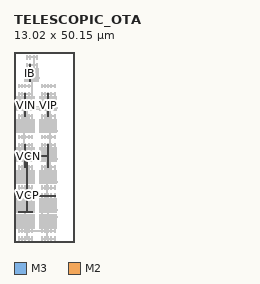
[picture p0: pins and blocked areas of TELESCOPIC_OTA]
MACRO TELESCOPIC_OTA
  ORIGIN 0 0 ;
  FOREIGN TELESCOPIC_OTA 0 0 ;
  SIZE 13.02 BY 50.15 ;
  PIN IB
    DIRECTION INOUT ;
    USE SIGNAL ;
    PORT 
      LAYER M3 ;
        RECT 4.16 42.26 4.44 46.78 ;
    END
  END IB
  PIN VCN
    DIRECTION INOUT ;
    USE SIGNAL ;
    PORT 
      LAYER M3 ;
        RECT 2.87 19.58 3.15 25.78 ;
      LAYER M3 ;
        RECT 8.89 19.58 9.17 25.78 ;
      LAYER M3 ;
        RECT 2.87 22.495 3.15 22.865 ;
      LAYER M2 ;
        RECT 3.01 22.54 9.03 22.82 ;
      LAYER M3 ;
        RECT 8.89 22.495 9.17 22.865 ;
    END
  END VCN
  PIN VOUT
    DIRECTION INOUT ;
    USE SIGNAL ;
    PORT 
      LAYER M2 ;
        RECT 1.12 7.84 4.9 8.12 ;
      LAYER M3 ;
        RECT 3.3 15.38 3.58 21.58 ;
      LAYER M2 ;
        RECT 3.28 7.84 3.6 8.12 ;
      LAYER M3 ;
        RECT 3.3 7.98 3.58 15.54 ;
    END
  END VOUT
  PIN VIP
    DIRECTION INOUT ;
    USE SIGNAL ;
    PORT 
      LAYER M3 ;
        RECT 8.89 33.02 9.17 39.22 ;
    END
  END VIP
  PIN VIN
    DIRECTION INOUT ;
    USE SIGNAL ;
    PORT 
      LAYER M3 ;
        RECT 2.87 33.02 3.15 39.22 ;
    END
  END VIN
  PIN VCP
    DIRECTION INOUT ;
    USE SIGNAL ;
    PORT 
      LAYER M2 ;
        RECT 1.12 12.04 4.9 12.32 ;
      LAYER M2 ;
        RECT 7.14 12.04 10.92 12.32 ;
      LAYER M2 ;
        RECT 4.73 12.04 7.31 12.32 ;
    END
  END VCP
  OBS 
  LAYER M3 ;
        RECT 3.3 29.24 3.58 35.44 ;
  LAYER M3 ;
        RECT 8.46 29.24 8.74 35.44 ;
  LAYER M2 ;
        RECT 4.13 42.7 5.33 42.98 ;
  LAYER M3 ;
        RECT 3.3 35.095 3.58 35.465 ;
  LAYER M4 ;
        RECT 3.44 34.88 8.6 35.68 ;
  LAYER M3 ;
        RECT 8.46 35.095 8.74 35.465 ;
  LAYER M4 ;
        RECT 4.565 34.88 4.895 35.68 ;
  LAYER M3 ;
        RECT 4.59 35.28 4.87 42.84 ;
  LAYER M2 ;
        RECT 4.57 42.7 4.89 42.98 ;
  LAYER M3 ;
        RECT 3.3 35.095 3.58 35.465 ;
  LAYER M4 ;
        RECT 3.275 34.88 3.605 35.68 ;
  LAYER M3 ;
        RECT 8.46 35.095 8.74 35.465 ;
  LAYER M4 ;
        RECT 8.435 34.88 8.765 35.68 ;
  LAYER M3 ;
        RECT 3.3 35.095 3.58 35.465 ;
  LAYER M4 ;
        RECT 3.275 34.88 3.605 35.68 ;
  LAYER M3 ;
        RECT 8.46 35.095 8.74 35.465 ;
  LAYER M4 ;
        RECT 8.435 34.88 8.765 35.68 ;
  LAYER M2 ;
        RECT 4.57 42.7 4.89 42.98 ;
  LAYER M3 ;
        RECT 4.59 42.68 4.87 43 ;
  LAYER M3 ;
        RECT 3.3 35.095 3.58 35.465 ;
  LAYER M4 ;
        RECT 3.275 34.88 3.605 35.68 ;
  LAYER M3 ;
        RECT 4.59 35.095 4.87 35.465 ;
  LAYER M4 ;
        RECT 4.565 34.88 4.895 35.68 ;
  LAYER M3 ;
        RECT 8.46 35.095 8.74 35.465 ;
  LAYER M4 ;
        RECT 8.435 34.88 8.765 35.68 ;
  LAYER M2 ;
        RECT 4.57 42.7 4.89 42.98 ;
  LAYER M3 ;
        RECT 4.59 42.68 4.87 43 ;
  LAYER M3 ;
        RECT 3.3 35.095 3.58 35.465 ;
  LAYER M4 ;
        RECT 3.275 34.88 3.605 35.68 ;
  LAYER M3 ;
        RECT 4.59 35.095 4.87 35.465 ;
  LAYER M4 ;
        RECT 4.565 34.88 4.895 35.68 ;
  LAYER M3 ;
        RECT 8.46 35.095 8.74 35.465 ;
  LAYER M4 ;
        RECT 8.435 34.88 8.765 35.68 ;
  LAYER M2 ;
        RECT 7.14 7 10.92 7.28 ;
  LAYER M2 ;
        RECT 6.71 8.26 11.35 8.54 ;
  LAYER M2 ;
        RECT 8.87 7 9.19 7.28 ;
  LAYER M3 ;
        RECT 8.89 7.14 9.17 8.4 ;
  LAYER M2 ;
        RECT 8.87 8.26 9.19 8.54 ;
  LAYER M2 ;
        RECT 8.87 7 9.19 7.28 ;
  LAYER M3 ;
        RECT 8.89 6.98 9.17 7.3 ;
  LAYER M2 ;
        RECT 8.87 8.26 9.19 8.54 ;
  LAYER M3 ;
        RECT 8.89 8.24 9.17 8.56 ;
  LAYER M2 ;
        RECT 8.87 7 9.19 7.28 ;
  LAYER M3 ;
        RECT 8.89 6.98 9.17 7.3 ;
  LAYER M2 ;
        RECT 8.87 8.26 9.19 8.54 ;
  LAYER M3 ;
        RECT 8.89 8.24 9.17 8.56 ;
  LAYER M2 ;
        RECT 1.12 2.8 4.9 3.08 ;
  LAYER M2 ;
        RECT 7.14 2.8 10.92 3.08 ;
  LAYER M2 ;
        RECT 7.14 7.84 10.92 8.12 ;
  LAYER M3 ;
        RECT 8.46 15.38 8.74 21.58 ;
  LAYER M2 ;
        RECT 4.73 2.8 7.31 3.08 ;
  LAYER M2 ;
        RECT 7.15 2.8 7.47 3.08 ;
  LAYER M3 ;
        RECT 7.17 2.94 7.45 7.98 ;
  LAYER M2 ;
        RECT 7.15 7.84 7.47 8.12 ;
  LAYER M2 ;
        RECT 8.44 7.84 8.76 8.12 ;
  LAYER M3 ;
        RECT 8.46 7.98 8.74 15.54 ;
  LAYER M2 ;
        RECT 7.15 2.8 7.47 3.08 ;
  LAYER M3 ;
        RECT 7.17 2.78 7.45 3.1 ;
  LAYER M2 ;
        RECT 7.15 7.84 7.47 8.12 ;
  LAYER M3 ;
        RECT 7.17 7.82 7.45 8.14 ;
  LAYER M2 ;
        RECT 7.15 2.8 7.47 3.08 ;
  LAYER M3 ;
        RECT 7.17 2.78 7.45 3.1 ;
  LAYER M2 ;
        RECT 7.15 7.84 7.47 8.12 ;
  LAYER M3 ;
        RECT 7.17 7.82 7.45 8.14 ;
  LAYER M2 ;
        RECT 7.15 2.8 7.47 3.08 ;
  LAYER M3 ;
        RECT 7.17 2.78 7.45 3.1 ;
  LAYER M2 ;
        RECT 7.15 7.84 7.47 8.12 ;
  LAYER M3 ;
        RECT 7.17 7.82 7.45 8.14 ;
  LAYER M2 ;
        RECT 8.44 7.84 8.76 8.12 ;
  LAYER M3 ;
        RECT 8.46 7.82 8.74 8.14 ;
  LAYER M2 ;
        RECT 7.15 2.8 7.47 3.08 ;
  LAYER M3 ;
        RECT 7.17 2.78 7.45 3.1 ;
  LAYER M2 ;
        RECT 7.15 7.84 7.47 8.12 ;
  LAYER M3 ;
        RECT 7.17 7.82 7.45 8.14 ;
  LAYER M2 ;
        RECT 8.44 7.84 8.76 8.12 ;
  LAYER M3 ;
        RECT 8.46 7.82 8.74 8.14 ;
  LAYER M2 ;
        RECT 1.12 7 4.9 7.28 ;
  LAYER M2 ;
        RECT 0.69 8.26 5.33 8.54 ;
  LAYER M2 ;
        RECT 2.85 7 3.17 7.28 ;
  LAYER M3 ;
        RECT 2.87 7.14 3.15 8.4 ;
  LAYER M2 ;
        RECT 2.85 8.26 3.17 8.54 ;
  LAYER M2 ;
        RECT 2.85 7 3.17 7.28 ;
  LAYER M3 ;
        RECT 2.87 6.98 3.15 7.3 ;
  LAYER M2 ;
        RECT 2.85 8.26 3.17 8.54 ;
  LAYER M3 ;
        RECT 2.87 8.24 3.15 8.56 ;
  LAYER M2 ;
        RECT 2.85 7 3.17 7.28 ;
  LAYER M3 ;
        RECT 2.87 6.98 3.15 7.3 ;
  LAYER M2 ;
        RECT 2.85 8.26 3.17 8.54 ;
  LAYER M3 ;
        RECT 2.87 8.24 3.15 8.56 ;
  LAYER M3 ;
        RECT 9.32 15.8 9.6 22 ;
  LAYER M3 ;
        RECT 9.32 28.82 9.6 35.02 ;
  LAYER M3 ;
        RECT 9.32 21.84 9.6 28.98 ;
  LAYER M3 ;
        RECT 2.44 15.8 2.72 22 ;
  LAYER M3 ;
        RECT 2.44 28.82 2.72 35.02 ;
  LAYER M3 ;
        RECT 2.44 21.84 2.72 28.98 ;
  LAYER M1 ;
        RECT 3.315 42.335 3.565 45.865 ;
  LAYER M1 ;
        RECT 3.315 46.115 3.565 47.125 ;
  LAYER M1 ;
        RECT 3.315 48.215 3.565 49.225 ;
  LAYER M1 ;
        RECT 2.885 42.335 3.135 45.865 ;
  LAYER M1 ;
        RECT 3.745 42.335 3.995 45.865 ;
  LAYER M1 ;
        RECT 4.175 42.335 4.425 45.865 ;
  LAYER M1 ;
        RECT 4.175 46.115 4.425 47.125 ;
  LAYER M1 ;
        RECT 4.175 48.215 4.425 49.225 ;
  LAYER M1 ;
        RECT 4.605 42.335 4.855 45.865 ;
  LAYER M1 ;
        RECT 5.035 42.335 5.285 45.865 ;
  LAYER M1 ;
        RECT 5.035 46.115 5.285 47.125 ;
  LAYER M1 ;
        RECT 5.035 48.215 5.285 49.225 ;
  LAYER M1 ;
        RECT 5.465 42.335 5.715 45.865 ;
  LAYER M1 ;
        RECT 5.895 42.335 6.145 45.865 ;
  LAYER M1 ;
        RECT 5.895 46.115 6.145 47.125 ;
  LAYER M1 ;
        RECT 5.895 48.215 6.145 49.225 ;
  LAYER M1 ;
        RECT 6.325 42.335 6.575 45.865 ;
  LAYER M2 ;
        RECT 3.27 42.28 6.19 42.56 ;
  LAYER M2 ;
        RECT 3.27 46.48 6.19 46.76 ;
  LAYER M2 ;
        RECT 2.84 43.12 6.62 43.4 ;
  LAYER M2 ;
        RECT 3.27 48.58 6.19 48.86 ;
  LAYER M3 ;
        RECT 4.16 42.26 4.44 46.78 ;
  LAYER M2 ;
        RECT 4.13 42.7 5.33 42.98 ;
  LAYER M3 ;
        RECT 5.02 43.1 5.3 48.88 ;
  LAYER M1 ;
        RECT 10.625 3.695 10.875 7.225 ;
  LAYER M1 ;
        RECT 10.625 2.435 10.875 3.445 ;
  LAYER M1 ;
        RECT 10.625 0.335 10.875 1.345 ;
  LAYER M1 ;
        RECT 11.055 3.695 11.305 7.225 ;
  LAYER M1 ;
        RECT 10.195 3.695 10.445 7.225 ;
  LAYER M1 ;
        RECT 9.765 3.695 10.015 7.225 ;
  LAYER M1 ;
        RECT 9.765 2.435 10.015 3.445 ;
  LAYER M1 ;
        RECT 9.765 0.335 10.015 1.345 ;
  LAYER M1 ;
        RECT 9.335 3.695 9.585 7.225 ;
  LAYER M1 ;
        RECT 8.905 3.695 9.155 7.225 ;
  LAYER M1 ;
        RECT 8.905 2.435 9.155 3.445 ;
  LAYER M1 ;
        RECT 8.905 0.335 9.155 1.345 ;
  LAYER M1 ;
        RECT 8.475 3.695 8.725 7.225 ;
  LAYER M1 ;
        RECT 8.045 3.695 8.295 7.225 ;
  LAYER M1 ;
        RECT 8.045 2.435 8.295 3.445 ;
  LAYER M1 ;
        RECT 8.045 0.335 8.295 1.345 ;
  LAYER M1 ;
        RECT 7.615 3.695 7.865 7.225 ;
  LAYER M1 ;
        RECT 7.185 3.695 7.435 7.225 ;
  LAYER M1 ;
        RECT 7.185 2.435 7.435 3.445 ;
  LAYER M1 ;
        RECT 7.185 0.335 7.435 1.345 ;
  LAYER M1 ;
        RECT 6.755 3.695 7.005 7.225 ;
  LAYER M2 ;
        RECT 6.71 6.58 11.35 6.86 ;
  LAYER M2 ;
        RECT 7.14 0.7 10.92 0.98 ;
  LAYER M2 ;
        RECT 7.14 7 10.92 7.28 ;
  LAYER M2 ;
        RECT 7.14 2.8 10.92 3.08 ;
  LAYER M3 ;
        RECT 8.46 0.68 8.74 6.88 ;
  LAYER M1 ;
        RECT 1.165 3.695 1.415 7.225 ;
  LAYER M1 ;
        RECT 1.165 2.435 1.415 3.445 ;
  LAYER M1 ;
        RECT 1.165 0.335 1.415 1.345 ;
  LAYER M1 ;
        RECT 0.735 3.695 0.985 7.225 ;
  LAYER M1 ;
        RECT 1.595 3.695 1.845 7.225 ;
  LAYER M1 ;
        RECT 2.025 3.695 2.275 7.225 ;
  LAYER M1 ;
        RECT 2.025 2.435 2.275 3.445 ;
  LAYER M1 ;
        RECT 2.025 0.335 2.275 1.345 ;
  LAYER M1 ;
        RECT 2.455 3.695 2.705 7.225 ;
  LAYER M1 ;
        RECT 2.885 3.695 3.135 7.225 ;
  LAYER M1 ;
        RECT 2.885 2.435 3.135 3.445 ;
  LAYER M1 ;
        RECT 2.885 0.335 3.135 1.345 ;
  LAYER M1 ;
        RECT 3.315 3.695 3.565 7.225 ;
  LAYER M1 ;
        RECT 3.745 3.695 3.995 7.225 ;
  LAYER M1 ;
        RECT 3.745 2.435 3.995 3.445 ;
  LAYER M1 ;
        RECT 3.745 0.335 3.995 1.345 ;
  LAYER M1 ;
        RECT 4.175 3.695 4.425 7.225 ;
  LAYER M1 ;
        RECT 4.605 3.695 4.855 7.225 ;
  LAYER M1 ;
        RECT 4.605 2.435 4.855 3.445 ;
  LAYER M1 ;
        RECT 4.605 0.335 4.855 1.345 ;
  LAYER M1 ;
        RECT 5.035 3.695 5.285 7.225 ;
  LAYER M2 ;
        RECT 0.69 6.58 5.33 6.86 ;
  LAYER M2 ;
        RECT 1.12 0.7 4.9 0.98 ;
  LAYER M2 ;
        RECT 1.12 7 4.9 7.28 ;
  LAYER M2 ;
        RECT 1.12 2.8 4.9 3.08 ;
  LAYER M3 ;
        RECT 3.3 0.68 3.58 6.88 ;
  LAYER M1 ;
        RECT 7.185 15.455 7.435 18.985 ;
  LAYER M1 ;
        RECT 7.185 19.235 7.435 20.245 ;
  LAYER M1 ;
        RECT 7.185 21.335 7.435 24.865 ;
  LAYER M1 ;
        RECT 7.185 25.115 7.435 26.125 ;
  LAYER M1 ;
        RECT 7.185 27.215 7.435 28.225 ;
  LAYER M1 ;
        RECT 6.755 15.455 7.005 18.985 ;
  LAYER M1 ;
        RECT 6.755 21.335 7.005 24.865 ;
  LAYER M1 ;
        RECT 7.615 15.455 7.865 18.985 ;
  LAYER M1 ;
        RECT 7.615 21.335 7.865 24.865 ;
  LAYER M1 ;
        RECT 8.045 15.455 8.295 18.985 ;
  LAYER M1 ;
        RECT 8.045 19.235 8.295 20.245 ;
  LAYER M1 ;
        RECT 8.045 21.335 8.295 24.865 ;
  LAYER M1 ;
        RECT 8.045 25.115 8.295 26.125 ;
  LAYER M1 ;
        RECT 8.045 27.215 8.295 28.225 ;
  LAYER M1 ;
        RECT 8.475 15.455 8.725 18.985 ;
  LAYER M1 ;
        RECT 8.475 21.335 8.725 24.865 ;
  LAYER M1 ;
        RECT 8.905 15.455 9.155 18.985 ;
  LAYER M1 ;
        RECT 8.905 19.235 9.155 20.245 ;
  LAYER M1 ;
        RECT 8.905 21.335 9.155 24.865 ;
  LAYER M1 ;
        RECT 8.905 25.115 9.155 26.125 ;
  LAYER M1 ;
        RECT 8.905 27.215 9.155 28.225 ;
  LAYER M1 ;
        RECT 9.335 15.455 9.585 18.985 ;
  LAYER M1 ;
        RECT 9.335 21.335 9.585 24.865 ;
  LAYER M1 ;
        RECT 9.765 15.455 10.015 18.985 ;
  LAYER M1 ;
        RECT 9.765 19.235 10.015 20.245 ;
  LAYER M1 ;
        RECT 9.765 21.335 10.015 24.865 ;
  LAYER M1 ;
        RECT 9.765 25.115 10.015 26.125 ;
  LAYER M1 ;
        RECT 9.765 27.215 10.015 28.225 ;
  LAYER M1 ;
        RECT 10.195 15.455 10.445 18.985 ;
  LAYER M1 ;
        RECT 10.195 21.335 10.445 24.865 ;
  LAYER M1 ;
        RECT 10.625 15.455 10.875 18.985 ;
  LAYER M1 ;
        RECT 10.625 19.235 10.875 20.245 ;
  LAYER M1 ;
        RECT 10.625 21.335 10.875 24.865 ;
  LAYER M1 ;
        RECT 10.625 25.115 10.875 26.125 ;
  LAYER M1 ;
        RECT 10.625 27.215 10.875 28.225 ;
  LAYER M1 ;
        RECT 11.055 15.455 11.305 18.985 ;
  LAYER M1 ;
        RECT 11.055 21.335 11.305 24.865 ;
  LAYER M2 ;
        RECT 7.14 15.4 10.92 15.68 ;
  LAYER M2 ;
        RECT 7.14 19.6 10.92 19.88 ;
  LAYER M2 ;
        RECT 6.71 15.82 11.35 16.1 ;
  LAYER M2 ;
        RECT 7.14 21.28 10.92 21.56 ;
  LAYER M2 ;
        RECT 7.14 25.48 10.92 25.76 ;
  LAYER M2 ;
        RECT 6.71 21.7 11.35 21.98 ;
  LAYER M2 ;
        RECT 7.14 27.58 10.92 27.86 ;
  LAYER M3 ;
        RECT 8.46 15.38 8.74 21.58 ;
  LAYER M3 ;
        RECT 8.89 19.58 9.17 25.78 ;
  LAYER M3 ;
        RECT 9.32 15.8 9.6 22 ;
  LAYER M1 ;
        RECT 4.605 15.455 4.855 18.985 ;
  LAYER M1 ;
        RECT 4.605 19.235 4.855 20.245 ;
  LAYER M1 ;
        RECT 4.605 21.335 4.855 24.865 ;
  LAYER M1 ;
        RECT 4.605 25.115 4.855 26.125 ;
  LAYER M1 ;
        RECT 4.605 27.215 4.855 28.225 ;
  LAYER M1 ;
        RECT 5.035 15.455 5.285 18.985 ;
  LAYER M1 ;
        RECT 5.035 21.335 5.285 24.865 ;
  LAYER M1 ;
        RECT 4.175 15.455 4.425 18.985 ;
  LAYER M1 ;
        RECT 4.175 21.335 4.425 24.865 ;
  LAYER M1 ;
        RECT 3.745 15.455 3.995 18.985 ;
  LAYER M1 ;
        RECT 3.745 19.235 3.995 20.245 ;
  LAYER M1 ;
        RECT 3.745 21.335 3.995 24.865 ;
  LAYER M1 ;
        RECT 3.745 25.115 3.995 26.125 ;
  LAYER M1 ;
        RECT 3.745 27.215 3.995 28.225 ;
  LAYER M1 ;
        RECT 3.315 15.455 3.565 18.985 ;
  LAYER M1 ;
        RECT 3.315 21.335 3.565 24.865 ;
  LAYER M1 ;
        RECT 2.885 15.455 3.135 18.985 ;
  LAYER M1 ;
        RECT 2.885 19.235 3.135 20.245 ;
  LAYER M1 ;
        RECT 2.885 21.335 3.135 24.865 ;
  LAYER M1 ;
        RECT 2.885 25.115 3.135 26.125 ;
  LAYER M1 ;
        RECT 2.885 27.215 3.135 28.225 ;
  LAYER M1 ;
        RECT 2.455 15.455 2.705 18.985 ;
  LAYER M1 ;
        RECT 2.455 21.335 2.705 24.865 ;
  LAYER M1 ;
        RECT 2.025 15.455 2.275 18.985 ;
  LAYER M1 ;
        RECT 2.025 19.235 2.275 20.245 ;
  LAYER M1 ;
        RECT 2.025 21.335 2.275 24.865 ;
  LAYER M1 ;
        RECT 2.025 25.115 2.275 26.125 ;
  LAYER M1 ;
        RECT 2.025 27.215 2.275 28.225 ;
  LAYER M1 ;
        RECT 1.595 15.455 1.845 18.985 ;
  LAYER M1 ;
        RECT 1.595 21.335 1.845 24.865 ;
  LAYER M1 ;
        RECT 1.165 15.455 1.415 18.985 ;
  LAYER M1 ;
        RECT 1.165 19.235 1.415 20.245 ;
  LAYER M1 ;
        RECT 1.165 21.335 1.415 24.865 ;
  LAYER M1 ;
        RECT 1.165 25.115 1.415 26.125 ;
  LAYER M1 ;
        RECT 1.165 27.215 1.415 28.225 ;
  LAYER M1 ;
        RECT 0.735 15.455 0.985 18.985 ;
  LAYER M1 ;
        RECT 0.735 21.335 0.985 24.865 ;
  LAYER M2 ;
        RECT 1.12 15.4 4.9 15.68 ;
  LAYER M2 ;
        RECT 1.12 19.6 4.9 19.88 ;
  LAYER M2 ;
        RECT 0.69 15.82 5.33 16.1 ;
  LAYER M2 ;
        RECT 1.12 21.28 4.9 21.56 ;
  LAYER M2 ;
        RECT 1.12 25.48 4.9 25.76 ;
  LAYER M2 ;
        RECT 0.69 21.7 5.33 21.98 ;
  LAYER M2 ;
        RECT 1.12 27.58 4.9 27.86 ;
  LAYER M3 ;
        RECT 3.3 15.38 3.58 21.58 ;
  LAYER M3 ;
        RECT 2.87 19.58 3.15 25.78 ;
  LAYER M3 ;
        RECT 2.44 15.8 2.72 22 ;
  LAYER M1 ;
        RECT 10.625 28.895 10.875 32.425 ;
  LAYER M1 ;
        RECT 10.625 32.675 10.875 33.685 ;
  LAYER M1 ;
        RECT 10.625 34.775 10.875 38.305 ;
  LAYER M1 ;
        RECT 10.625 38.555 10.875 39.565 ;
  LAYER M1 ;
        RECT 10.625 40.655 10.875 41.665 ;
  LAYER M1 ;
        RECT 11.055 28.895 11.305 32.425 ;
  LAYER M1 ;
        RECT 11.055 34.775 11.305 38.305 ;
  LAYER M1 ;
        RECT 10.195 28.895 10.445 32.425 ;
  LAYER M1 ;
        RECT 10.195 34.775 10.445 38.305 ;
  LAYER M1 ;
        RECT 9.765 28.895 10.015 32.425 ;
  LAYER M1 ;
        RECT 9.765 32.675 10.015 33.685 ;
  LAYER M1 ;
        RECT 9.765 34.775 10.015 38.305 ;
  LAYER M1 ;
        RECT 9.765 38.555 10.015 39.565 ;
  LAYER M1 ;
        RECT 9.765 40.655 10.015 41.665 ;
  LAYER M1 ;
        RECT 9.335 28.895 9.585 32.425 ;
  LAYER M1 ;
        RECT 9.335 34.775 9.585 38.305 ;
  LAYER M1 ;
        RECT 8.905 28.895 9.155 32.425 ;
  LAYER M1 ;
        RECT 8.905 32.675 9.155 33.685 ;
  LAYER M1 ;
        RECT 8.905 34.775 9.155 38.305 ;
  LAYER M1 ;
        RECT 8.905 38.555 9.155 39.565 ;
  LAYER M1 ;
        RECT 8.905 40.655 9.155 41.665 ;
  LAYER M1 ;
        RECT 8.475 28.895 8.725 32.425 ;
  LAYER M1 ;
        RECT 8.475 34.775 8.725 38.305 ;
  LAYER M1 ;
        RECT 8.045 28.895 8.295 32.425 ;
  LAYER M1 ;
        RECT 8.045 32.675 8.295 33.685 ;
  LAYER M1 ;
        RECT 8.045 34.775 8.295 38.305 ;
  LAYER M1 ;
        RECT 8.045 38.555 8.295 39.565 ;
  LAYER M1 ;
        RECT 8.045 40.655 8.295 41.665 ;
  LAYER M1 ;
        RECT 7.615 28.895 7.865 32.425 ;
  LAYER M1 ;
        RECT 7.615 34.775 7.865 38.305 ;
  LAYER M1 ;
        RECT 7.185 28.895 7.435 32.425 ;
  LAYER M1 ;
        RECT 7.185 32.675 7.435 33.685 ;
  LAYER M1 ;
        RECT 7.185 34.775 7.435 38.305 ;
  LAYER M1 ;
        RECT 7.185 38.555 7.435 39.565 ;
  LAYER M1 ;
        RECT 7.185 40.655 7.435 41.665 ;
  LAYER M1 ;
        RECT 6.755 28.895 7.005 32.425 ;
  LAYER M1 ;
        RECT 6.755 34.775 7.005 38.305 ;
  LAYER M2 ;
        RECT 7.14 28.84 10.92 29.12 ;
  LAYER M2 ;
        RECT 7.14 33.04 10.92 33.32 ;
  LAYER M2 ;
        RECT 6.71 29.26 11.35 29.54 ;
  LAYER M2 ;
        RECT 7.14 34.72 10.92 35 ;
  LAYER M2 ;
        RECT 7.14 38.92 10.92 39.2 ;
  LAYER M2 ;
        RECT 6.71 35.14 11.35 35.42 ;
  LAYER M2 ;
        RECT 7.14 41.02 10.92 41.3 ;
  LAYER M3 ;
        RECT 9.32 28.82 9.6 35.02 ;
  LAYER M3 ;
        RECT 8.89 33.02 9.17 39.22 ;
  LAYER M3 ;
        RECT 8.46 29.24 8.74 35.44 ;
  LAYER M1 ;
        RECT 1.165 28.895 1.415 32.425 ;
  LAYER M1 ;
        RECT 1.165 32.675 1.415 33.685 ;
  LAYER M1 ;
        RECT 1.165 34.775 1.415 38.305 ;
  LAYER M1 ;
        RECT 1.165 38.555 1.415 39.565 ;
  LAYER M1 ;
        RECT 1.165 40.655 1.415 41.665 ;
  LAYER M1 ;
        RECT 0.735 28.895 0.985 32.425 ;
  LAYER M1 ;
        RECT 0.735 34.775 0.985 38.305 ;
  LAYER M1 ;
        RECT 1.595 28.895 1.845 32.425 ;
  LAYER M1 ;
        RECT 1.595 34.775 1.845 38.305 ;
  LAYER M1 ;
        RECT 2.025 28.895 2.275 32.425 ;
  LAYER M1 ;
        RECT 2.025 32.675 2.275 33.685 ;
  LAYER M1 ;
        RECT 2.025 34.775 2.275 38.305 ;
  LAYER M1 ;
        RECT 2.025 38.555 2.275 39.565 ;
  LAYER M1 ;
        RECT 2.025 40.655 2.275 41.665 ;
  LAYER M1 ;
        RECT 2.455 28.895 2.705 32.425 ;
  LAYER M1 ;
        RECT 2.455 34.775 2.705 38.305 ;
  LAYER M1 ;
        RECT 2.885 28.895 3.135 32.425 ;
  LAYER M1 ;
        RECT 2.885 32.675 3.135 33.685 ;
  LAYER M1 ;
        RECT 2.885 34.775 3.135 38.305 ;
  LAYER M1 ;
        RECT 2.885 38.555 3.135 39.565 ;
  LAYER M1 ;
        RECT 2.885 40.655 3.135 41.665 ;
  LAYER M1 ;
        RECT 3.315 28.895 3.565 32.425 ;
  LAYER M1 ;
        RECT 3.315 34.775 3.565 38.305 ;
  LAYER M1 ;
        RECT 3.745 28.895 3.995 32.425 ;
  LAYER M1 ;
        RECT 3.745 32.675 3.995 33.685 ;
  LAYER M1 ;
        RECT 3.745 34.775 3.995 38.305 ;
  LAYER M1 ;
        RECT 3.745 38.555 3.995 39.565 ;
  LAYER M1 ;
        RECT 3.745 40.655 3.995 41.665 ;
  LAYER M1 ;
        RECT 4.175 28.895 4.425 32.425 ;
  LAYER M1 ;
        RECT 4.175 34.775 4.425 38.305 ;
  LAYER M1 ;
        RECT 4.605 28.895 4.855 32.425 ;
  LAYER M1 ;
        RECT 4.605 32.675 4.855 33.685 ;
  LAYER M1 ;
        RECT 4.605 34.775 4.855 38.305 ;
  LAYER M1 ;
        RECT 4.605 38.555 4.855 39.565 ;
  LAYER M1 ;
        RECT 4.605 40.655 4.855 41.665 ;
  LAYER M1 ;
        RECT 5.035 28.895 5.285 32.425 ;
  LAYER M1 ;
        RECT 5.035 34.775 5.285 38.305 ;
  LAYER M2 ;
        RECT 1.12 28.84 4.9 29.12 ;
  LAYER M2 ;
        RECT 1.12 33.04 4.9 33.32 ;
  LAYER M2 ;
        RECT 0.69 29.26 5.33 29.54 ;
  LAYER M2 ;
        RECT 1.12 34.72 4.9 35 ;
  LAYER M2 ;
        RECT 1.12 38.92 4.9 39.2 ;
  LAYER M2 ;
        RECT 0.69 35.14 5.33 35.42 ;
  LAYER M2 ;
        RECT 1.12 41.02 4.9 41.3 ;
  LAYER M3 ;
        RECT 2.44 28.82 2.72 35.02 ;
  LAYER M3 ;
        RECT 2.87 33.02 3.15 39.22 ;
  LAYER M3 ;
        RECT 3.3 29.24 3.58 35.44 ;
  LAYER M1 ;
        RECT 7.185 7.895 7.435 11.425 ;
  LAYER M1 ;
        RECT 7.185 11.675 7.435 12.685 ;
  LAYER M1 ;
        RECT 7.185 13.775 7.435 14.785 ;
  LAYER M1 ;
        RECT 6.755 7.895 7.005 11.425 ;
  LAYER M1 ;
        RECT 7.615 7.895 7.865 11.425 ;
  LAYER M1 ;
        RECT 8.045 7.895 8.295 11.425 ;
  LAYER M1 ;
        RECT 8.045 11.675 8.295 12.685 ;
  LAYER M1 ;
        RECT 8.045 13.775 8.295 14.785 ;
  LAYER M1 ;
        RECT 8.475 7.895 8.725 11.425 ;
  LAYER M1 ;
        RECT 8.905 7.895 9.155 11.425 ;
  LAYER M1 ;
        RECT 8.905 11.675 9.155 12.685 ;
  LAYER M1 ;
        RECT 8.905 13.775 9.155 14.785 ;
  LAYER M1 ;
        RECT 9.335 7.895 9.585 11.425 ;
  LAYER M1 ;
        RECT 9.765 7.895 10.015 11.425 ;
  LAYER M1 ;
        RECT 9.765 11.675 10.015 12.685 ;
  LAYER M1 ;
        RECT 9.765 13.775 10.015 14.785 ;
  LAYER M1 ;
        RECT 10.195 7.895 10.445 11.425 ;
  LAYER M1 ;
        RECT 10.625 7.895 10.875 11.425 ;
  LAYER M1 ;
        RECT 10.625 11.675 10.875 12.685 ;
  LAYER M1 ;
        RECT 10.625 13.775 10.875 14.785 ;
  LAYER M1 ;
        RECT 11.055 7.895 11.305 11.425 ;
  LAYER M2 ;
        RECT 7.14 14.14 10.92 14.42 ;
  LAYER M2 ;
        RECT 7.14 7.84 10.92 8.12 ;
  LAYER M2 ;
        RECT 7.14 12.04 10.92 12.32 ;
  LAYER M2 ;
        RECT 6.71 8.26 11.35 8.54 ;
  LAYER M1 ;
        RECT 4.605 7.895 4.855 11.425 ;
  LAYER M1 ;
        RECT 4.605 11.675 4.855 12.685 ;
  LAYER M1 ;
        RECT 4.605 13.775 4.855 14.785 ;
  LAYER M1 ;
        RECT 5.035 7.895 5.285 11.425 ;
  LAYER M1 ;
        RECT 4.175 7.895 4.425 11.425 ;
  LAYER M1 ;
        RECT 3.745 7.895 3.995 11.425 ;
  LAYER M1 ;
        RECT 3.745 11.675 3.995 12.685 ;
  LAYER M1 ;
        RECT 3.745 13.775 3.995 14.785 ;
  LAYER M1 ;
        RECT 3.315 7.895 3.565 11.425 ;
  LAYER M1 ;
        RECT 2.885 7.895 3.135 11.425 ;
  LAYER M1 ;
        RECT 2.885 11.675 3.135 12.685 ;
  LAYER M1 ;
        RECT 2.885 13.775 3.135 14.785 ;
  LAYER M1 ;
        RECT 2.455 7.895 2.705 11.425 ;
  LAYER M1 ;
        RECT 2.025 7.895 2.275 11.425 ;
  LAYER M1 ;
        RECT 2.025 11.675 2.275 12.685 ;
  LAYER M1 ;
        RECT 2.025 13.775 2.275 14.785 ;
  LAYER M1 ;
        RECT 1.595 7.895 1.845 11.425 ;
  LAYER M1 ;
        RECT 1.165 7.895 1.415 11.425 ;
  LAYER M1 ;
        RECT 1.165 11.675 1.415 12.685 ;
  LAYER M1 ;
        RECT 1.165 13.775 1.415 14.785 ;
  LAYER M1 ;
        RECT 0.735 7.895 0.985 11.425 ;
  LAYER M2 ;
        RECT 1.12 14.14 4.9 14.42 ;
  LAYER M2 ;
        RECT 1.12 7.84 4.9 8.12 ;
  LAYER M2 ;
        RECT 1.12 12.04 4.9 12.32 ;
  LAYER M2 ;
        RECT 0.69 8.26 5.33 8.54 ;
  END 
END TELESCOPIC_OTA
